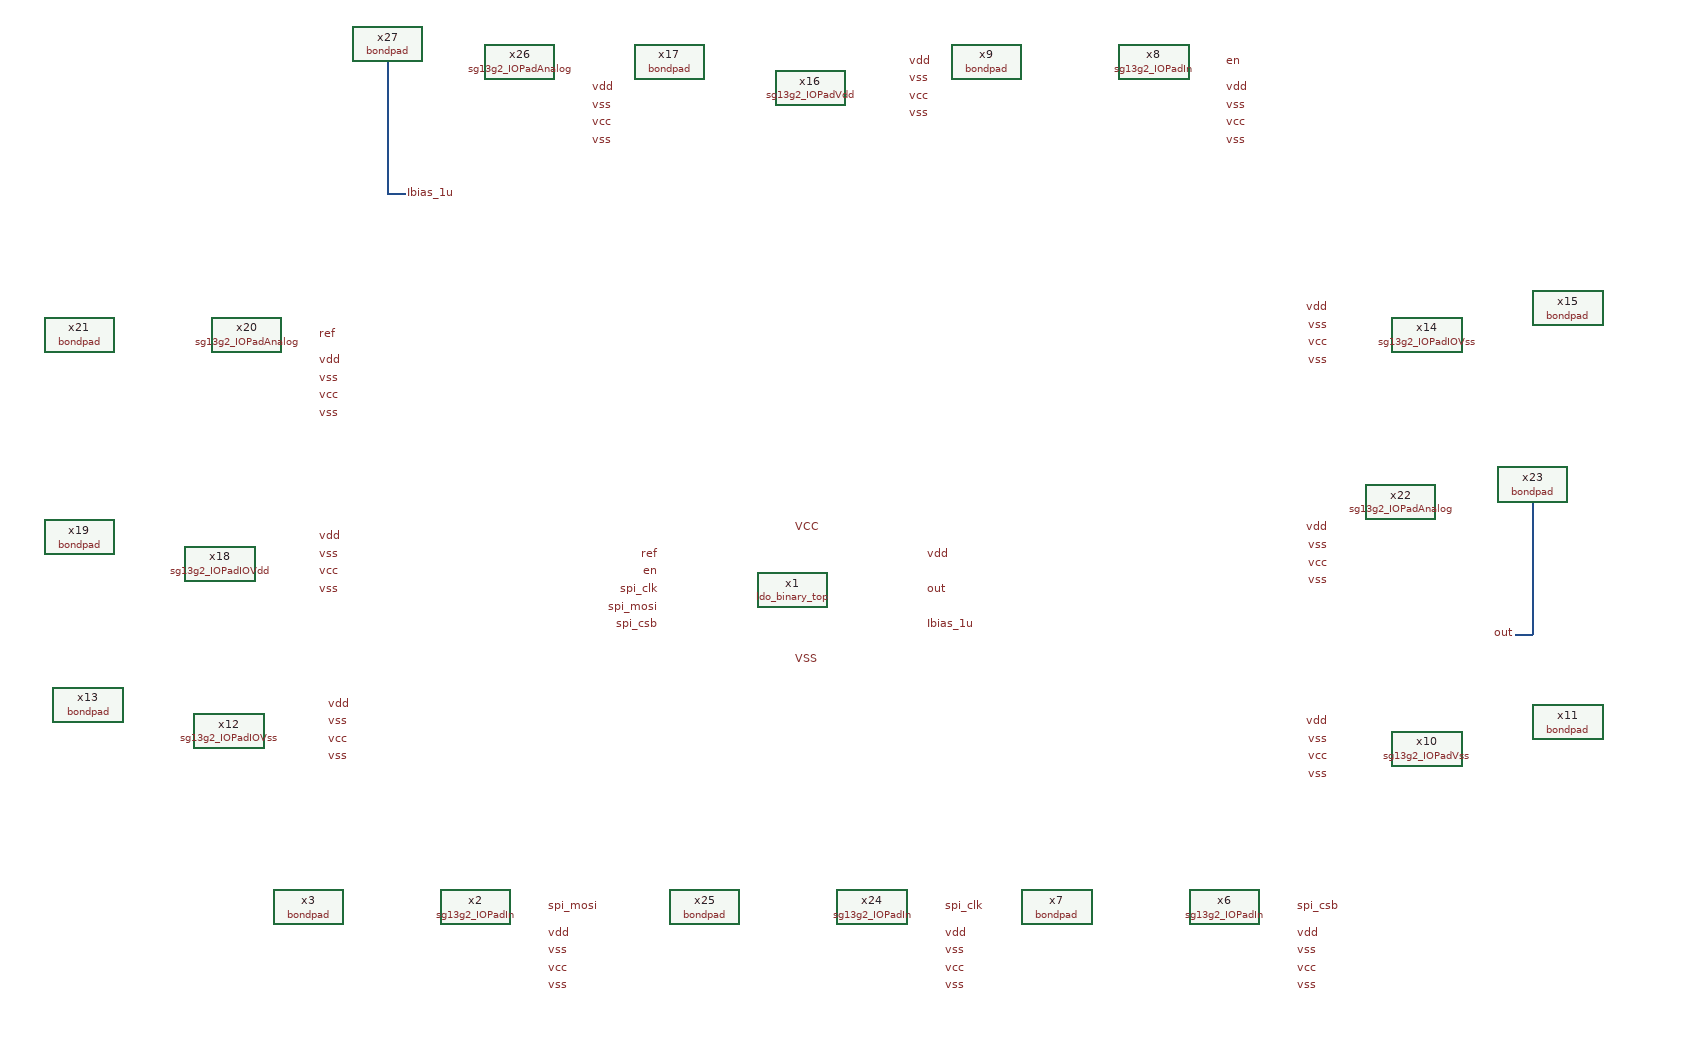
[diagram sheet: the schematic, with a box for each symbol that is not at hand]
v {xschem version=3.4.8RC file_version=1.2}
G {}
K {}
V {}
S {}
F {}
E {}
N 1470 -930 1490 -930 {lab=Ibias_1u}
N 1470 -1080 1470 -930 {lab=Ibias_1u}
N 2750 -430 2770 -430 {lab=out}
N 2770 -580 2770 -430 {lab=out}
C {ldo_binary_top.sym} 1930 -480 0 0 {name=x1}
C {sg13g2_IOPadIn.sym} 1570 -120 0 0 {name=x2}
C {bondpad.sym} 1380 -120 0 0 {name=x3}
C {sg13g2_IOPadIn.sym} 2420 -120 0 0 {name=x6}
C {bondpad.sym} 2230 -120 0 0 {name=x7}
C {lab_pin.sym} 1930 -550 0 1 {name=p1 lab=VCC}
C {lab_pin.sym} 1930 -400 0 1 {name=p2 lab=VSS}
C {lab_pin.sym} 1780 -480 0 0 {name=p3 lab=spi_clk}
C {lab_pin.sym} 1780 -460 0 0 {name=p4 lab=spi_mosi}
C {lab_pin.sym} 1780 -440 0 0 {name=p5 lab=spi_csb}
C {lab_pin.sym} 1780 -520 0 0 {name=p6 lab=ref}
C {lab_pin.sym} 1780 -500 0 0 {name=p7 lab=en}
C {lab_pin.sym} 2080 -480 0 1 {name=p8 lab=out}
C {lab_pin.sym} 2080 -440 0 1 {name=p9 lab=Ibias_1u}
C {lab_pin.sym} 2080 -520 0 1 {name=p10 lab=vdd}
C {lab_pin.sym} 1650 -120 0 1 {name=p11 lab=spi_mosi}
C {lab_pin.sym} 2500 -120 0 1 {name=p13 lab=spi_csb}
C {sg13g2_IOPadIn.sym} 2340 -1080 0 0 {name=x8}
C {bondpad.sym} 2150 -1080 0 0 {name=x9}
C {lab_pin.sym} 2420 -1080 0 1 {name=p14 lab=en}
C {sg13g2_IOPadVss.sym} 2650 -300 0 1 {name=x10}
C {bondpad.sym} 2810 -330 0 1 {name=x11}
C {sg13g2_IOPadIOVss.sym} 1290 -320 0 0 {name=x12}
C {bondpad.sym} 1130 -350 0 0 {name=x13}
C {sg13g2_IOPadIOVss.sym} 2650 -770 0 1 {name=x14}
C {bondpad.sym} 2810 -800 0 1 {name=x15}
C {sg13g2_IOPadVdd.sym} 1950 -1050 0 0 {name=x16}
C {bondpad.sym} 1790 -1080 0 0 {name=x17}
C {lab_pin.sym} 2060 -1080 0 1 {name=p18 lab=vdd}
C {sg13g2_IOPadIOVdd.sym} 1280 -510 0 0 {name=x18}
C {bondpad.sym} 1120 -540 0 0 {name=x19}
C {sg13g2_IOPadAnalog.sym} 1310 -770 0 0 {name=x20}
C {bondpad.sym} 1120 -770 0 0 {name=x21}
C {lab_pin.sym} 1390 -770 0 1 {name=p20 lab=ref}
C {lab_pin.sym} 1490 -930 0 1 {name=p21 lab=Ibias_1u}
C {lab_pin.sym} 1390 -700 0 1 {name=p23 lab=vcc}
C {lab_pin.sym} 1390 -680 0 1 {name=p24 lab=vss}
C {lab_pin.sym} 1390 -740 0 1 {name=p25 lab=vdd}
C {lab_pin.sym} 1390 -720 0 1 {name=p26 lab=vss}
C {sg13g2_IOPadAnalog.sym} 1620 -1080 0 0 {name=x26}
C {bondpad.sym} 1430 -1080 0 0 {name=x27}
C {lab_pin.sym} 1700 -1010 0 1 {name=p28 lab=vcc}
C {lab_pin.sym} 1700 -990 0 1 {name=p29 lab=vss}
C {lab_pin.sym} 1700 -1050 0 1 {name=p30 lab=vdd}
C {lab_pin.sym} 1700 -1030 0 1 {name=p31 lab=vss}
C {lab_pin.sym} 2750 -430 0 0 {name=p32 lab=out}
C {sg13g2_IOPadAnalog.sym} 2620 -580 0 1 {name=x22}
C {bondpad.sym} 2810 -580 0 1 {name=x23}
C {lab_pin.sym} 2540 -510 0 0 {name=p34 lab=vcc}
C {lab_pin.sym} 2540 -490 0 0 {name=p35 lab=vss}
C {lab_pin.sym} 2540 -550 0 0 {name=p36 lab=vdd}
C {lab_pin.sym} 2540 -530 0 0 {name=p37 lab=vss}
C {sg13g2_IOPadIn.sym} 2020 -120 0 0 {name=x24}
C {bondpad.sym} 1830 -120 0 0 {name=x25}
C {lab_pin.sym} 2100 -120 0 1 {name=p22 lab=spi_clk}
C {lab_pin.sym} 1650 -50 0 1 {name=p38 lab=vcc}
C {lab_pin.sym} 1650 -30 0 1 {name=p39 lab=vss}
C {lab_pin.sym} 1650 -90 0 1 {name=p40 lab=vdd}
C {lab_pin.sym} 1650 -70 0 1 {name=p41 lab=vss}
C {lab_pin.sym} 2100 -50 0 1 {name=p42 lab=vcc}
C {lab_pin.sym} 2100 -30 0 1 {name=p43 lab=vss}
C {lab_pin.sym} 2100 -90 0 1 {name=p44 lab=vdd}
C {lab_pin.sym} 2100 -70 0 1 {name=p45 lab=vss}
C {lab_pin.sym} 2500 -50 0 1 {name=p12 lab=vcc}
C {lab_pin.sym} 2500 -30 0 1 {name=p46 lab=vss}
C {lab_pin.sym} 2500 -90 0 1 {name=p47 lab=vdd}
C {lab_pin.sym} 2500 -70 0 1 {name=p48 lab=vss}
C {lab_pin.sym} 2420 -1010 0 1 {name=p49 lab=vcc}
C {lab_pin.sym} 2420 -990 0 1 {name=p50 lab=vss}
C {lab_pin.sym} 2420 -1050 0 1 {name=p51 lab=vdd}
C {lab_pin.sym} 2420 -1030 0 1 {name=p52 lab=vss}
C {lab_pin.sym} 1390 -500 0 1 {name=p19 lab=vcc}
C {lab_pin.sym} 1390 -480 0 1 {name=p53 lab=vss}
C {lab_pin.sym} 1390 -540 0 1 {name=p54 lab=vdd}
C {lab_pin.sym} 1390 -520 0 1 {name=p55 lab=vss}
C {lab_pin.sym} 2060 -1040 0 1 {name=p56 lab=vcc}
C {lab_pin.sym} 2060 -1020 0 1 {name=p57 lab=vss}
C {lab_pin.sym} 2060 -1060 0 1 {name=p58 lab=vss}
C {lab_pin.sym} 2540 -290 0 0 {name=p27 lab=vcc}
C {lab_pin.sym} 2540 -270 0 0 {name=p33 lab=vss}
C {lab_pin.sym} 2540 -330 0 0 {name=p59 lab=vdd}
C {lab_pin.sym} 2540 -310 0 0 {name=p60 lab=vss}
C {lab_pin.sym} 2540 -760 0 0 {name=p15 lab=vcc}
C {lab_pin.sym} 2540 -740 0 0 {name=p16 lab=vss}
C {lab_pin.sym} 2540 -800 0 0 {name=p17 lab=vdd}
C {lab_pin.sym} 2540 -780 0 0 {name=p61 lab=vss}
C {lab_pin.sym} 1400 -310 0 1 {name=p62 lab=vcc}
C {lab_pin.sym} 1400 -290 0 1 {name=p63 lab=vss}
C {lab_pin.sym} 1400 -350 0 1 {name=p64 lab=vdd}
C {lab_pin.sym} 1400 -330 0 1 {name=p65 lab=vss}
